VERSION 5.7 ;
  NOWIREEXTENSIONATPIN ON ;
  DIVIDERCHAR "/" ;
  BUSBITCHARS "[]" ;
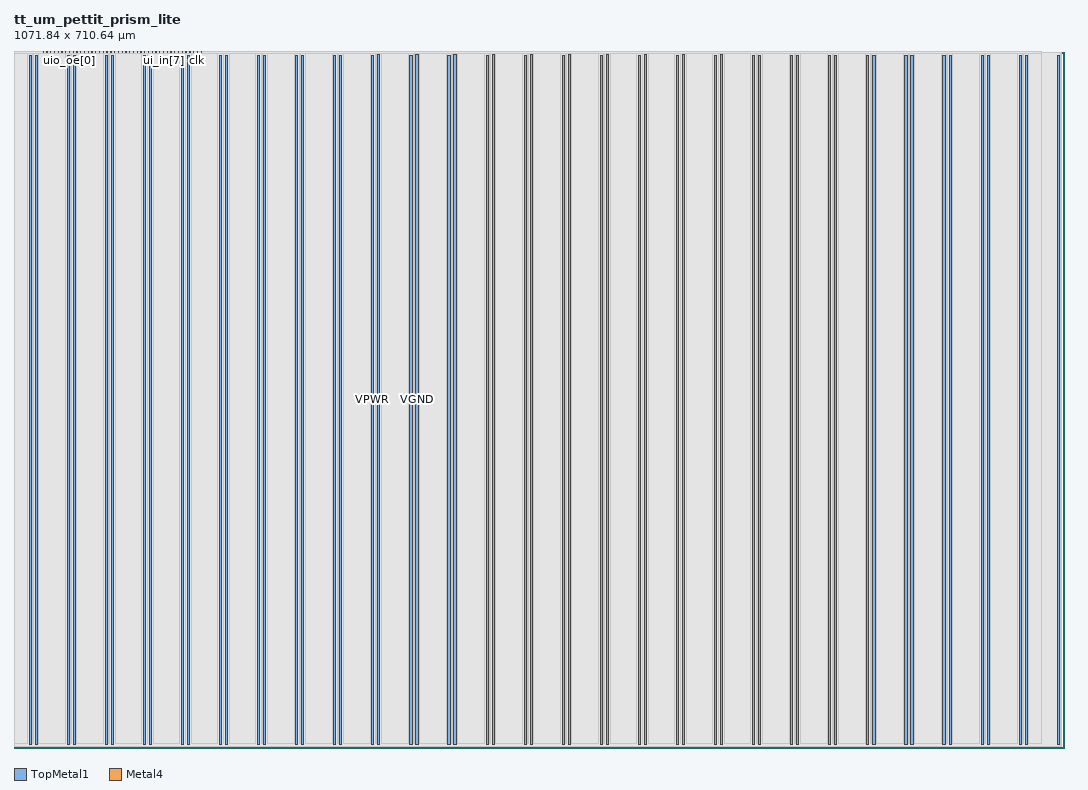
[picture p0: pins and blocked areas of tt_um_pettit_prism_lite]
MACRO tt_um_pettit_prism_lite
  CLASS BLOCK ;
  FOREIGN tt_um_pettit_prism_lite ;
  ORIGIN 0.000 0.000 ;
  SIZE 1071.840 BY 710.640 ;
  PIN VGND
    DIRECTION INOUT ;
    USE GROUND ;
    PORT
      LAYER TopMetal1 ;
        RECT 21.580 3.780 23.780 706.860 ;
    END
    PORT
      LAYER TopMetal1 ;
        RECT 60.450 3.780 62.650 706.860 ;
    END
    PORT
      LAYER TopMetal1 ;
        RECT 99.320 3.780 101.520 706.860 ;
    END
    PORT
      LAYER TopMetal1 ;
        RECT 138.190 3.780 140.390 706.860 ;
    END
    PORT
      LAYER TopMetal1 ;
        RECT 177.060 3.780 179.260 706.860 ;
    END
    PORT
      LAYER TopMetal1 ;
        RECT 215.930 3.780 218.130 706.860 ;
    END
    PORT
      LAYER TopMetal1 ;
        RECT 254.800 3.780 257.000 706.860 ;
    END
    PORT
      LAYER TopMetal1 ;
        RECT 293.670 3.780 295.870 706.860 ;
    END
    PORT
      LAYER TopMetal1 ;
        RECT 332.540 3.560 334.740 707.080 ;
    END
    PORT
      LAYER TopMetal1 ;
        RECT 371.410 3.150 373.610 707.490 ;
    END
    PORT
      LAYER TopMetal1 ;
        RECT 410.280 3.150 412.480 707.490 ;
    END
    PORT
      LAYER TopMetal1 ;
        RECT 449.150 3.150 451.350 707.490 ;
    END
    PORT
      LAYER TopMetal1 ;
        RECT 488.020 3.150 490.220 707.490 ;
    END
    PORT
      LAYER TopMetal1 ;
        RECT 526.890 3.150 529.090 707.490 ;
    END
    PORT
      LAYER TopMetal1 ;
        RECT 565.760 3.150 567.960 707.490 ;
    END
    PORT
      LAYER TopMetal1 ;
        RECT 604.630 3.150 606.830 707.490 ;
    END
    PORT
      LAYER TopMetal1 ;
        RECT 643.500 3.150 645.700 707.490 ;
    END
    PORT
      LAYER TopMetal1 ;
        RECT 682.370 3.150 684.570 707.490 ;
    END
    PORT
      LAYER TopMetal1 ;
        RECT 721.240 3.150 723.440 707.490 ;
    END
    PORT
      LAYER TopMetal1 ;
        RECT 760.110 3.780 762.310 706.860 ;
    END
    PORT
      LAYER TopMetal1 ;
        RECT 798.980 3.780 801.180 706.860 ;
    END
    PORT
      LAYER TopMetal1 ;
        RECT 837.850 3.780 840.050 706.860 ;
    END
    PORT
      LAYER TopMetal1 ;
        RECT 876.720 3.780 878.920 706.860 ;
    END
    PORT
      LAYER TopMetal1 ;
        RECT 915.590 3.780 917.790 706.860 ;
    END
    PORT
      LAYER TopMetal1 ;
        RECT 954.460 3.780 956.660 706.860 ;
    END
    PORT
      LAYER TopMetal1 ;
        RECT 993.330 3.780 995.530 706.860 ;
    END
    PORT
      LAYER TopMetal1 ;
        RECT 1032.200 3.780 1034.400 706.860 ;
    END
  END VGND
  PIN VPWR
    DIRECTION INOUT ;
    USE POWER ;
    PORT
      LAYER TopMetal1 ;
        RECT 15.380 3.780 17.580 706.860 ;
    END
    PORT
      LAYER TopMetal1 ;
        RECT 54.250 3.780 56.450 706.860 ;
    END
    PORT
      LAYER TopMetal1 ;
        RECT 93.120 3.780 95.320 706.860 ;
    END
    PORT
      LAYER TopMetal1 ;
        RECT 131.990 3.780 134.190 706.860 ;
    END
    PORT
      LAYER TopMetal1 ;
        RECT 170.860 3.780 173.060 706.860 ;
    END
    PORT
      LAYER TopMetal1 ;
        RECT 209.730 3.780 211.930 706.860 ;
    END
    PORT
      LAYER TopMetal1 ;
        RECT 248.600 3.780 250.800 706.860 ;
    END
    PORT
      LAYER TopMetal1 ;
        RECT 287.470 3.780 289.670 706.860 ;
    END
    PORT
      LAYER TopMetal1 ;
        RECT 326.340 3.780 328.540 706.860 ;
    END
    PORT
      LAYER TopMetal1 ;
        RECT 365.210 3.560 367.410 707.080 ;
    END
    PORT
      LAYER TopMetal1 ;
        RECT 404.080 3.560 406.280 707.080 ;
    END
    PORT
      LAYER TopMetal1 ;
        RECT 442.950 3.560 445.150 707.080 ;
    END
    PORT
      LAYER TopMetal1 ;
        RECT 481.820 3.560 484.020 707.080 ;
    END
    PORT
      LAYER TopMetal1 ;
        RECT 520.690 3.560 522.890 707.080 ;
    END
    PORT
      LAYER TopMetal1 ;
        RECT 559.560 3.560 561.760 707.080 ;
    END
    PORT
      LAYER TopMetal1 ;
        RECT 598.430 3.560 600.630 707.080 ;
    END
    PORT
      LAYER TopMetal1 ;
        RECT 637.300 3.560 639.500 707.080 ;
    END
    PORT
      LAYER TopMetal1 ;
        RECT 676.170 3.560 678.370 707.080 ;
    END
    PORT
      LAYER TopMetal1 ;
        RECT 715.040 3.560 717.240 707.080 ;
    END
    PORT
      LAYER TopMetal1 ;
        RECT 753.910 3.780 756.110 706.860 ;
    END
    PORT
      LAYER TopMetal1 ;
        RECT 792.780 3.780 794.980 706.860 ;
    END
    PORT
      LAYER TopMetal1 ;
        RECT 831.650 3.780 833.850 706.860 ;
    END
    PORT
      LAYER TopMetal1 ;
        RECT 870.520 3.780 872.720 706.860 ;
    END
    PORT
      LAYER TopMetal1 ;
        RECT 909.390 3.780 911.590 706.860 ;
    END
    PORT
      LAYER TopMetal1 ;
        RECT 948.260 3.780 950.460 706.860 ;
    END
    PORT
      LAYER TopMetal1 ;
        RECT 987.130 3.780 989.330 706.860 ;
    END
    PORT
      LAYER TopMetal1 ;
        RECT 1026.000 3.780 1028.200 706.860 ;
    END
    PORT
      LAYER TopMetal1 ;
        RECT 1064.870 3.780 1067.070 706.860 ;
    END
  END VPWR
  PIN clk
    DIRECTION INPUT ;
    USE SIGNAL ;
    ANTENNAGATEAREA 1.450800 ;
    PORT
      LAYER Metal4 ;
        RECT 187.050 709.640 187.350 710.640 ;
    END
  END clk
  PIN ena
    DIRECTION INPUT ;
    USE SIGNAL ;
    PORT
      LAYER Metal4 ;
        RECT 190.890 709.640 191.190 710.640 ;
    END
  END ena
  PIN rst_n
    DIRECTION INPUT ;
    USE SIGNAL ;
    ANTENNAGATEAREA 0.180700 ;
    PORT
      LAYER Metal4 ;
        RECT 183.210 709.640 183.510 710.640 ;
    END
  END rst_n
  PIN ui_in[0]
    DIRECTION INPUT ;
    USE SIGNAL ;
    ANTENNAGATEAREA 0.180700 ;
    PORT
      LAYER Metal4 ;
        RECT 179.370 709.640 179.670 710.640 ;
    END
  END ui_in[0]
  PIN ui_in[1]
    DIRECTION INPUT ;
    USE SIGNAL ;
    ANTENNAGATEAREA 0.180700 ;
    PORT
      LAYER Metal4 ;
        RECT 175.530 709.640 175.830 710.640 ;
    END
  END ui_in[1]
  PIN ui_in[2]
    DIRECTION INPUT ;
    USE SIGNAL ;
    ANTENNAGATEAREA 0.180700 ;
    ANTENNADIFFAREA 2.015400 ;
    PORT
      LAYER Metal4 ;
        RECT 171.690 709.640 171.990 710.640 ;
    END
  END ui_in[2]
  PIN ui_in[3]
    DIRECTION INPUT ;
    USE SIGNAL ;
    ANTENNAGATEAREA 0.180700 ;
    ANTENNADIFFAREA 2.015400 ;
    PORT
      LAYER Metal4 ;
        RECT 167.850 709.640 168.150 710.640 ;
    END
  END ui_in[3]
  PIN ui_in[4]
    DIRECTION INPUT ;
    USE SIGNAL ;
    ANTENNAGATEAREA 0.180700 ;
    PORT
      LAYER Metal4 ;
        RECT 164.010 709.640 164.310 710.640 ;
    END
  END ui_in[4]
  PIN ui_in[5]
    DIRECTION INPUT ;
    USE SIGNAL ;
    ANTENNAGATEAREA 0.180700 ;
    PORT
      LAYER Metal4 ;
        RECT 160.170 709.640 160.470 710.640 ;
    END
  END ui_in[5]
  PIN ui_in[6]
    DIRECTION INPUT ;
    USE SIGNAL ;
    ANTENNAGATEAREA 0.180700 ;
    PORT
      LAYER Metal4 ;
        RECT 156.330 709.640 156.630 710.640 ;
    END
  END ui_in[6]
  PIN ui_in[7]
    DIRECTION INPUT ;
    USE SIGNAL ;
    ANTENNAGATEAREA 0.180700 ;
    PORT
      LAYER Metal4 ;
        RECT 152.490 709.640 152.790 710.640 ;
    END
  END ui_in[7]
  PIN uio_in[0]
    DIRECTION INPUT ;
    USE SIGNAL ;
    PORT
      LAYER Metal4 ;
        RECT 148.650 709.640 148.950 710.640 ;
    END
  END uio_in[0]
  PIN uio_in[1]
    DIRECTION INPUT ;
    USE SIGNAL ;
    ANTENNAGATEAREA 0.180700 ;
    PORT
      LAYER Metal4 ;
        RECT 144.810 709.640 145.110 710.640 ;
    END
  END uio_in[1]
  PIN uio_in[2]
    DIRECTION INPUT ;
    USE SIGNAL ;
    ANTENNAGATEAREA 0.180700 ;
    PORT
      LAYER Metal4 ;
        RECT 140.970 709.640 141.270 710.640 ;
    END
  END uio_in[2]
  PIN uio_in[3]
    DIRECTION INPUT ;
    USE SIGNAL ;
    PORT
      LAYER Metal4 ;
        RECT 137.130 709.640 137.430 710.640 ;
    END
  END uio_in[3]
  PIN uio_in[4]
    DIRECTION INPUT ;
    USE SIGNAL ;
    ANTENNAGATEAREA 0.180700 ;
    PORT
      LAYER Metal4 ;
        RECT 133.290 709.640 133.590 710.640 ;
    END
  END uio_in[4]
  PIN uio_in[5]
    DIRECTION INPUT ;
    USE SIGNAL ;
    ANTENNAGATEAREA 0.180700 ;
    PORT
      LAYER Metal4 ;
        RECT 129.450 709.640 129.750 710.640 ;
    END
  END uio_in[5]
  PIN uio_in[6]
    DIRECTION INPUT ;
    USE SIGNAL ;
    PORT
      LAYER Metal4 ;
        RECT 125.610 709.640 125.910 710.640 ;
    END
  END uio_in[6]
  PIN uio_in[7]
    DIRECTION INPUT ;
    USE SIGNAL ;
    PORT
      LAYER Metal4 ;
        RECT 121.770 709.640 122.070 710.640 ;
    END
  END uio_in[7]
  PIN uio_oe[0]
    DIRECTION OUTPUT ;
    USE SIGNAL ;
    ANTENNADIFFAREA 0.632400 ;
    PORT
      LAYER Metal4 ;
        RECT 56.490 709.640 56.790 710.640 ;
    END
  END uio_oe[0]
  PIN uio_oe[1]
    DIRECTION OUTPUT ;
    USE SIGNAL ;
    ANTENNADIFFAREA 0.632400 ;
    PORT
      LAYER Metal4 ;
        RECT 52.650 709.640 52.950 710.640 ;
    END
  END uio_oe[1]
  PIN uio_oe[2]
    DIRECTION OUTPUT ;
    USE SIGNAL ;
    ANTENNADIFFAREA 0.632400 ;
    PORT
      LAYER Metal4 ;
        RECT 48.810 709.640 49.110 710.640 ;
    END
  END uio_oe[2]
  PIN uio_oe[3]
    DIRECTION OUTPUT ;
    USE SIGNAL ;
    ANTENNADIFFAREA 0.632400 ;
    PORT
      LAYER Metal4 ;
        RECT 44.970 709.640 45.270 710.640 ;
    END
  END uio_oe[3]
  PIN uio_oe[4]
    DIRECTION OUTPUT ;
    USE SIGNAL ;
    ANTENNADIFFAREA 0.632400 ;
    PORT
      LAYER Metal4 ;
        RECT 41.130 709.640 41.430 710.640 ;
    END
  END uio_oe[4]
  PIN uio_oe[5]
    DIRECTION OUTPUT ;
    USE SIGNAL ;
    ANTENNADIFFAREA 0.632400 ;
    PORT
      LAYER Metal4 ;
        RECT 37.290 709.640 37.590 710.640 ;
    END
  END uio_oe[5]
  PIN uio_oe[6]
    DIRECTION OUTPUT ;
    USE SIGNAL ;
    ANTENNADIFFAREA 0.632400 ;
    PORT
      LAYER Metal4 ;
        RECT 33.450 709.640 33.750 710.640 ;
    END
  END uio_oe[6]
  PIN uio_oe[7]
    DIRECTION OUTPUT ;
    USE SIGNAL ;
    ANTENNADIFFAREA 0.632400 ;
    PORT
      LAYER Metal4 ;
        RECT 29.610 709.640 29.910 710.640 ;
    END
  END uio_oe[7]
  PIN uio_out[0]
    DIRECTION OUTPUT ;
    USE SIGNAL ;
    ANTENNAGATEAREA 0.744900 ;
    ANTENNADIFFAREA 0.632400 ;
    PORT
      LAYER Metal4 ;
        RECT 87.210 709.640 87.510 710.640 ;
    END
  END uio_out[0]
  PIN uio_out[1]
    DIRECTION OUTPUT ;
    USE SIGNAL ;
    ANTENNADIFFAREA 1.058000 ;
    PORT
      LAYER Metal4 ;
        RECT 83.370 709.640 83.670 710.640 ;
    END
  END uio_out[1]
  PIN uio_out[2]
    DIRECTION OUTPUT ;
    USE SIGNAL ;
    ANTENNADIFFAREA 0.677200 ;
    PORT
      LAYER Metal4 ;
        RECT 79.530 709.640 79.830 710.640 ;
    END
  END uio_out[2]
  PIN uio_out[3]
    DIRECTION OUTPUT ;
    USE SIGNAL ;
    ANTENNADIFFAREA 0.677200 ;
    PORT
      LAYER Metal4 ;
        RECT 75.690 709.640 75.990 710.640 ;
    END
  END uio_out[3]
  PIN uio_out[4]
    DIRECTION OUTPUT ;
    USE SIGNAL ;
    ANTENNADIFFAREA 0.632400 ;
    PORT
      LAYER Metal4 ;
        RECT 71.850 709.640 72.150 710.640 ;
    END
  END uio_out[4]
  PIN uio_out[5]
    DIRECTION OUTPUT ;
    USE SIGNAL ;
    ANTENNADIFFAREA 1.058000 ;
    PORT
      LAYER Metal4 ;
        RECT 68.010 709.640 68.310 710.640 ;
    END
  END uio_out[5]
  PIN uio_out[6]
    DIRECTION OUTPUT ;
    USE SIGNAL ;
    ANTENNAGATEAREA 0.109200 ;
    ANTENNADIFFAREA 0.632400 ;
    PORT
      LAYER Metal4 ;
        RECT 64.170 709.640 64.470 710.640 ;
    END
  END uio_out[6]
  PIN uio_out[7]
    DIRECTION OUTPUT ;
    USE SIGNAL ;
    ANTENNAGATEAREA 0.109200 ;
    ANTENNADIFFAREA 0.632400 ;
    PORT
      LAYER Metal4 ;
        RECT 60.330 709.640 60.630 710.640 ;
    END
  END uio_out[7]
  PIN uo_out[0]
    DIRECTION OUTPUT ;
    USE SIGNAL ;
    ANTENNADIFFAREA 0.706800 ;
    PORT
      LAYER Metal4 ;
        RECT 117.930 709.640 118.230 710.640 ;
    END
  END uo_out[0]
  PIN uo_out[1]
    DIRECTION OUTPUT ;
    USE SIGNAL ;
    ANTENNADIFFAREA 0.706800 ;
    PORT
      LAYER Metal4 ;
        RECT 114.090 709.640 114.390 710.640 ;
    END
  END uo_out[1]
  PIN uo_out[2]
    DIRECTION OUTPUT ;
    USE SIGNAL ;
    ANTENNADIFFAREA 0.615900 ;
    PORT
      LAYER Metal4 ;
        RECT 110.250 709.640 110.550 710.640 ;
    END
  END uo_out[2]
  PIN uo_out[3]
    DIRECTION OUTPUT ;
    USE SIGNAL ;
    ANTENNADIFFAREA 0.632400 ;
    PORT
      LAYER Metal4 ;
        RECT 106.410 709.640 106.710 710.640 ;
    END
  END uo_out[3]
  PIN uo_out[4]
    DIRECTION OUTPUT ;
    USE SIGNAL ;
    ANTENNADIFFAREA 0.632400 ;
    PORT
      LAYER Metal4 ;
        RECT 102.570 709.640 102.870 710.640 ;
    END
  END uo_out[4]
  PIN uo_out[5]
    DIRECTION OUTPUT ;
    USE SIGNAL ;
    ANTENNADIFFAREA 0.615900 ;
    PORT
      LAYER Metal4 ;
        RECT 98.730 709.640 99.030 710.640 ;
    END
  END uo_out[5]
  PIN uo_out[6]
    DIRECTION OUTPUT ;
    USE SIGNAL ;
    ANTENNADIFFAREA 0.706800 ;
    PORT
      LAYER Metal4 ;
        RECT 94.890 709.640 95.190 710.640 ;
    END
  END uo_out[6]
  PIN uo_out[7]
    DIRECTION OUTPUT ;
    USE SIGNAL ;
    ANTENNADIFFAREA 0.706800 ;
    PORT
      LAYER Metal4 ;
        RECT 91.050 709.640 91.350 710.640 ;
    END
  END uo_out[7]
  OBS
      LAYER GatPoly ;
        RECT 2.880 3.630 1068.960 707.010 ;
      LAYER Metal1 ;
        RECT 2.880 3.560 1068.960 707.080 ;
      LAYER Metal2 ;
        RECT 0.375 1.535 1069.065 709.525 ;
      LAYER Metal3 ;
        RECT 0.335 1.575 1069.105 709.485 ;
      LAYER Metal4 ;
        RECT 0.380 709.430 29.400 709.900 ;
        RECT 30.120 709.430 33.240 709.900 ;
        RECT 33.960 709.430 37.080 709.900 ;
        RECT 37.800 709.430 40.920 709.900 ;
        RECT 41.640 709.430 44.760 709.900 ;
        RECT 45.480 709.430 48.600 709.900 ;
        RECT 49.320 709.430 52.440 709.900 ;
        RECT 53.160 709.430 56.280 709.900 ;
        RECT 57.000 709.430 60.120 709.900 ;
        RECT 60.840 709.430 63.960 709.900 ;
        RECT 64.680 709.430 67.800 709.900 ;
        RECT 68.520 709.430 71.640 709.900 ;
        RECT 72.360 709.430 75.480 709.900 ;
        RECT 76.200 709.430 79.320 709.900 ;
        RECT 80.040 709.430 83.160 709.900 ;
        RECT 83.880 709.430 87.000 709.900 ;
        RECT 87.720 709.430 90.840 709.900 ;
        RECT 91.560 709.430 94.680 709.900 ;
        RECT 95.400 709.430 98.520 709.900 ;
        RECT 99.240 709.430 102.360 709.900 ;
        RECT 103.080 709.430 106.200 709.900 ;
        RECT 106.920 709.430 110.040 709.900 ;
        RECT 110.760 709.430 113.880 709.900 ;
        RECT 114.600 709.430 117.720 709.900 ;
        RECT 118.440 709.430 121.560 709.900 ;
        RECT 122.280 709.430 125.400 709.900 ;
        RECT 126.120 709.430 129.240 709.900 ;
        RECT 129.960 709.430 133.080 709.900 ;
        RECT 133.800 709.430 136.920 709.900 ;
        RECT 137.640 709.430 140.760 709.900 ;
        RECT 141.480 709.430 144.600 709.900 ;
        RECT 145.320 709.430 148.440 709.900 ;
        RECT 149.160 709.430 152.280 709.900 ;
        RECT 153.000 709.430 156.120 709.900 ;
        RECT 156.840 709.430 159.960 709.900 ;
        RECT 160.680 709.430 163.800 709.900 ;
        RECT 164.520 709.430 167.640 709.900 ;
        RECT 168.360 709.430 171.480 709.900 ;
        RECT 172.200 709.430 175.320 709.900 ;
        RECT 176.040 709.430 179.160 709.900 ;
        RECT 179.880 709.430 183.000 709.900 ;
        RECT 183.720 709.430 186.840 709.900 ;
        RECT 187.560 709.430 190.680 709.900 ;
        RECT 191.400 709.430 1068.585 709.900 ;
        RECT 0.380 1.530 1068.585 709.430 ;
      LAYER Metal5 ;
        RECT 0.815 2.000 1068.625 710.110 ;
      LAYER TopMetal1 ;
        RECT 0.820 709.130 1048.980 710.620 ;
        RECT 0.820 708.720 369.770 709.130 ;
        RECT 0.820 708.500 330.900 708.720 ;
        RECT 0.820 4.640 13.740 708.500 ;
        RECT 19.220 4.640 19.940 708.500 ;
        RECT 25.420 4.640 52.610 708.500 ;
        RECT 58.090 4.640 58.810 708.500 ;
        RECT 64.290 4.640 91.480 708.500 ;
        RECT 96.960 4.640 97.680 708.500 ;
        RECT 103.160 4.640 130.350 708.500 ;
        RECT 135.830 4.640 136.550 708.500 ;
        RECT 142.030 4.640 169.220 708.500 ;
        RECT 174.700 4.640 175.420 708.500 ;
        RECT 180.900 4.640 208.090 708.500 ;
        RECT 213.570 4.640 214.290 708.500 ;
        RECT 219.770 4.640 246.960 708.500 ;
        RECT 252.440 4.640 253.160 708.500 ;
        RECT 258.640 4.640 285.830 708.500 ;
        RECT 291.310 4.640 292.030 708.500 ;
        RECT 297.510 4.640 324.700 708.500 ;
        RECT 330.180 4.640 330.900 708.500 ;
        RECT 336.380 4.640 363.570 708.720 ;
        RECT 369.050 4.640 369.770 708.720 ;
        RECT 375.250 708.720 408.640 709.130 ;
        RECT 375.250 4.640 402.440 708.720 ;
        RECT 407.920 4.640 408.640 708.720 ;
        RECT 414.120 708.720 447.510 709.130 ;
        RECT 414.120 4.640 441.310 708.720 ;
        RECT 446.790 4.640 447.510 708.720 ;
        RECT 452.990 708.720 486.380 709.130 ;
        RECT 452.990 4.640 480.180 708.720 ;
        RECT 485.660 4.640 486.380 708.720 ;
        RECT 491.860 708.720 525.250 709.130 ;
        RECT 491.860 4.640 519.050 708.720 ;
        RECT 524.530 4.640 525.250 708.720 ;
        RECT 530.730 708.720 564.120 709.130 ;
        RECT 530.730 4.640 557.920 708.720 ;
        RECT 563.400 4.640 564.120 708.720 ;
        RECT 569.600 708.720 602.990 709.130 ;
        RECT 569.600 4.640 596.790 708.720 ;
        RECT 602.270 4.640 602.990 708.720 ;
        RECT 608.470 708.720 641.860 709.130 ;
        RECT 608.470 4.640 635.660 708.720 ;
        RECT 641.140 4.640 641.860 708.720 ;
        RECT 647.340 708.720 680.730 709.130 ;
        RECT 647.340 4.640 674.530 708.720 ;
        RECT 680.010 4.640 680.730 708.720 ;
        RECT 686.210 708.720 719.600 709.130 ;
        RECT 686.210 4.640 713.400 708.720 ;
        RECT 718.880 4.640 719.600 708.720 ;
        RECT 725.080 708.500 1048.980 709.130 ;
        RECT 725.080 4.640 752.270 708.500 ;
        RECT 757.750 4.640 758.470 708.500 ;
        RECT 763.950 4.640 791.140 708.500 ;
        RECT 796.620 4.640 797.340 708.500 ;
        RECT 802.820 4.640 830.010 708.500 ;
        RECT 835.490 4.640 836.210 708.500 ;
        RECT 841.690 4.640 868.880 708.500 ;
        RECT 874.360 4.640 875.080 708.500 ;
        RECT 880.560 4.640 907.750 708.500 ;
        RECT 913.230 4.640 913.950 708.500 ;
        RECT 919.430 4.640 946.620 708.500 ;
        RECT 952.100 4.640 952.820 708.500 ;
        RECT 958.300 4.640 985.490 708.500 ;
        RECT 990.970 4.640 991.690 708.500 ;
        RECT 997.170 4.640 1024.360 708.500 ;
        RECT 1029.840 4.640 1030.560 708.500 ;
        RECT 1036.040 4.640 1048.980 708.500 ;
  END
END tt_um_pettit_prism_lite
END LIBRARY

